VERSION 5.8 ;
BUSBITCHARS "[]" ;
DIVIDERCHAR "/" ;
UNITS
    DATABASE MICRONS 1000 ;
END UNITS

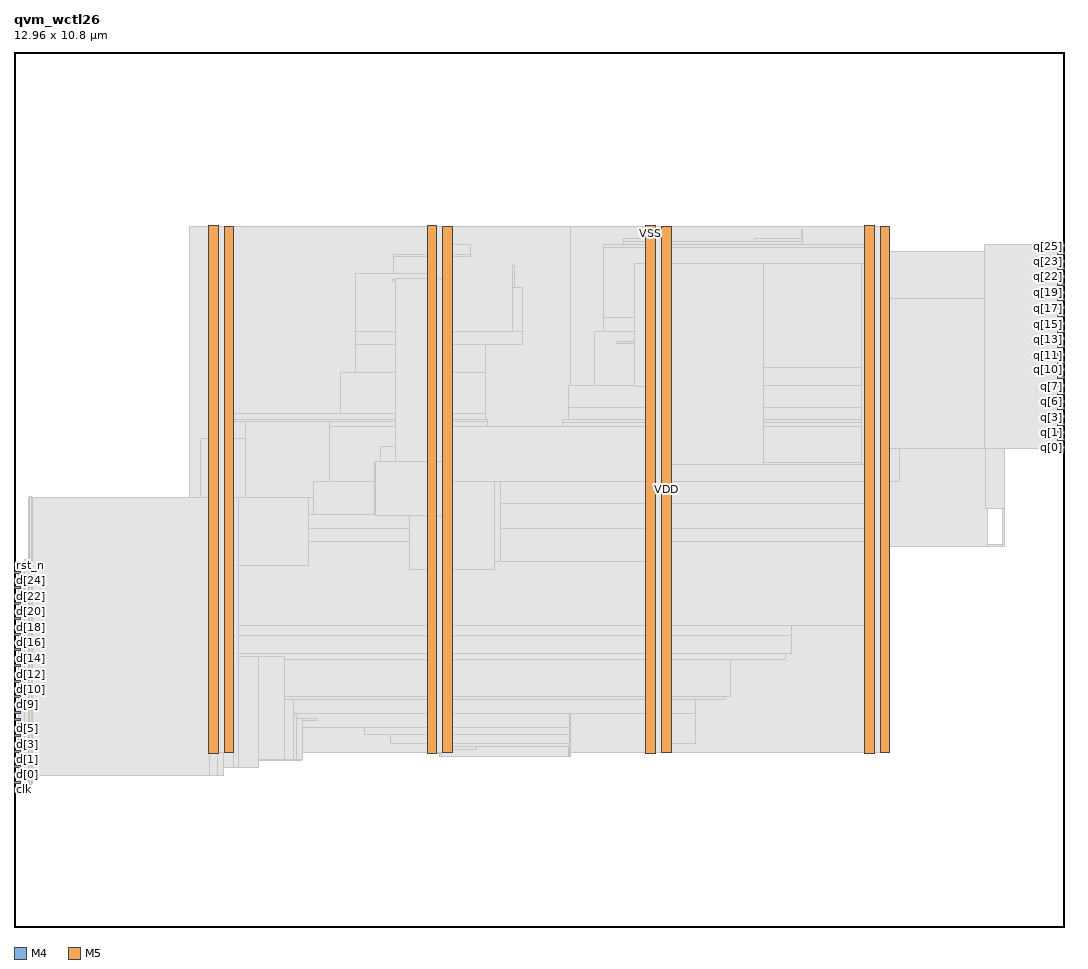
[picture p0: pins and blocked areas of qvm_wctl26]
MACRO qvm_wctl26
  FOREIGN qvm_wctl26 0 0 ;
  CLASS BLOCK ;
  SIZE 12.96 BY 10.8 ;
  PIN clk
    DIRECTION INPUT ;
    USE SIGNAL ;
    PORT
      LAYER M4 ;
        RECT  0 1.776 0.084 1.8 ;
    END
  END clk
  PIN d[0]
    DIRECTION INPUT ;
    USE SIGNAL ;
    PORT
      LAYER M4 ;
        RECT  0 1.872 0.084 1.896 ;
    END
  END d[0]
  PIN d[10]
    DIRECTION INPUT ;
    USE SIGNAL ;
    PORT
      LAYER M4 ;
        RECT  0 2.832 0.084 2.856 ;
    END
  END d[10]
  PIN d[11]
    DIRECTION INPUT ;
    USE SIGNAL ;
    PORT
      LAYER M4 ;
        RECT  0 2.928 0.084 2.952 ;
    END
  END d[11]
  PIN d[12]
    DIRECTION INPUT ;
    USE SIGNAL ;
    PORT
      LAYER M4 ;
        RECT  0 3.024 0.084 3.048 ;
    END
  END d[12]
  PIN d[13]
    DIRECTION INPUT ;
    USE SIGNAL ;
    PORT
      LAYER M4 ;
        RECT  0 3.12 0.084 3.144 ;
    END
  END d[13]
  PIN d[14]
    DIRECTION INPUT ;
    USE SIGNAL ;
    PORT
      LAYER M4 ;
        RECT  0 3.216 0.084 3.24 ;
    END
  END d[14]
  PIN d[15]
    DIRECTION INPUT ;
    USE SIGNAL ;
    PORT
      LAYER M4 ;
        RECT  0 3.312 0.084 3.336 ;
    END
  END d[15]
  PIN d[16]
    DIRECTION INPUT ;
    USE SIGNAL ;
    PORT
      LAYER M4 ;
        RECT  0 3.408 0.084 3.432 ;
    END
  END d[16]
  PIN d[17]
    DIRECTION INPUT ;
    USE SIGNAL ;
    PORT
      LAYER M4 ;
        RECT  0 3.504 0.084 3.528 ;
    END
  END d[17]
  PIN d[18]
    DIRECTION INPUT ;
    USE SIGNAL ;
    PORT
      LAYER M4 ;
        RECT  0 3.6 0.084 3.624 ;
    END
  END d[18]
  PIN d[19]
    DIRECTION INPUT ;
    USE SIGNAL ;
    PORT
      LAYER M4 ;
        RECT  0 3.696 0.084 3.72 ;
    END
  END d[19]
  PIN d[1]
    DIRECTION INPUT ;
    USE SIGNAL ;
    PORT
      LAYER M4 ;
        RECT  0 1.968 0.084 1.992 ;
    END
  END d[1]
  PIN d[20]
    DIRECTION INPUT ;
    USE SIGNAL ;
    PORT
      LAYER M4 ;
        RECT  0 3.792 0.084 3.816 ;
    END
  END d[20]
  PIN d[21]
    DIRECTION INPUT ;
    USE SIGNAL ;
    PORT
      LAYER M4 ;
        RECT  0 3.888 0.084 3.912 ;
    END
  END d[21]
  PIN d[22]
    DIRECTION INPUT ;
    USE SIGNAL ;
    PORT
      LAYER M4 ;
        RECT  0 3.984 0.084 4.008 ;
    END
  END d[22]
  PIN d[23]
    DIRECTION INPUT ;
    USE SIGNAL ;
    PORT
      LAYER M4 ;
        RECT  0 4.08 0.084 4.104 ;
    END
  END d[23]
  PIN d[24]
    DIRECTION INPUT ;
    USE SIGNAL ;
    PORT
      LAYER M4 ;
        RECT  0 4.176 0.084 4.2 ;
    END
  END d[24]
  PIN d[25]
    DIRECTION INPUT ;
    USE SIGNAL ;
    PORT
      LAYER M4 ;
        RECT  0 4.272 0.084 4.296 ;
    END
  END d[25]
  PIN d[2]
    DIRECTION INPUT ;
    USE SIGNAL ;
    PORT
      LAYER M4 ;
        RECT  0 2.064 0.084 2.088 ;
    END
  END d[2]
  PIN d[3]
    DIRECTION INPUT ;
    USE SIGNAL ;
    PORT
      LAYER M4 ;
        RECT  0 2.16 0.084 2.184 ;
    END
  END d[3]
  PIN d[4]
    DIRECTION INPUT ;
    USE SIGNAL ;
    PORT
      LAYER M4 ;
        RECT  0 2.256 0.084 2.28 ;
    END
  END d[4]
  PIN d[5]
    DIRECTION INPUT ;
    USE SIGNAL ;
    PORT
      LAYER M4 ;
        RECT  0 2.352 0.084 2.376 ;
    END
  END d[5]
  PIN d[6]
    DIRECTION INPUT ;
    USE SIGNAL ;
    PORT
      LAYER M4 ;
        RECT  0 2.448 0.084 2.472 ;
    END
  END d[6]
  PIN d[7]
    DIRECTION INPUT ;
    USE SIGNAL ;
    PORT
      LAYER M4 ;
        RECT  0 2.544 0.084 2.568 ;
    END
  END d[7]
  PIN d[8]
    DIRECTION INPUT ;
    USE SIGNAL ;
    PORT
      LAYER M4 ;
        RECT  0 2.64 0.084 2.664 ;
    END
  END d[8]
  PIN d[9]
    DIRECTION INPUT ;
    USE SIGNAL ;
    PORT
      LAYER M4 ;
        RECT  0 2.736 0.084 2.76 ;
    END
  END d[9]
  PIN q[0]
    DIRECTION OUTPUT ;
    USE SIGNAL ;
    PORT
      LAYER M4 ;
        RECT  12.876 5.904 12.96 5.928 ;
    END
  END q[0]
  PIN q[10]
    DIRECTION OUTPUT ;
    USE SIGNAL ;
    PORT
      LAYER M4 ;
        RECT  12.876 6.864 12.96 6.888 ;
    END
  END q[10]
  PIN q[11]
    DIRECTION OUTPUT ;
    USE SIGNAL ;
    PORT
      LAYER M4 ;
        RECT  12.876 6.96 12.96 6.984 ;
    END
  END q[11]
  PIN q[12]
    DIRECTION OUTPUT ;
    USE SIGNAL ;
    PORT
      LAYER M4 ;
        RECT  12.876 7.056 12.96 7.08 ;
    END
  END q[12]
  PIN q[13]
    DIRECTION OUTPUT ;
    USE SIGNAL ;
    PORT
      LAYER M4 ;
        RECT  12.876 7.152 12.96 7.176 ;
    END
  END q[13]
  PIN q[14]
    DIRECTION OUTPUT ;
    USE SIGNAL ;
    PORT
      LAYER M4 ;
        RECT  12.876 7.248 12.96 7.272 ;
    END
  END q[14]
  PIN q[15]
    DIRECTION OUTPUT ;
    USE SIGNAL ;
    PORT
      LAYER M4 ;
        RECT  12.876 7.344 12.96 7.368 ;
    END
  END q[15]
  PIN q[16]
    DIRECTION OUTPUT ;
    USE SIGNAL ;
    PORT
      LAYER M4 ;
        RECT  12.876 7.44 12.96 7.464 ;
    END
  END q[16]
  PIN q[17]
    DIRECTION OUTPUT ;
    USE SIGNAL ;
    PORT
      LAYER M4 ;
        RECT  12.876 7.536 12.96 7.56 ;
    END
  END q[17]
  PIN q[18]
    DIRECTION OUTPUT ;
    USE SIGNAL ;
    PORT
      LAYER M4 ;
        RECT  12.876 7.632 12.96 7.656 ;
    END
  END q[18]
  PIN q[19]
    DIRECTION OUTPUT ;
    USE SIGNAL ;
    PORT
      LAYER M4 ;
        RECT  12.876 7.728 12.96 7.752 ;
    END
  END q[19]
  PIN q[1]
    DIRECTION OUTPUT ;
    USE SIGNAL ;
    PORT
      LAYER M4 ;
        RECT  12.876 6 12.96 6.024 ;
    END
  END q[1]
  PIN q[20]
    DIRECTION OUTPUT ;
    USE SIGNAL ;
    PORT
      LAYER M4 ;
        RECT  12.876 7.824 12.96 7.848 ;
    END
  END q[20]
  PIN q[21]
    DIRECTION OUTPUT ;
    USE SIGNAL ;
    PORT
      LAYER M4 ;
        RECT  12.876 7.92 12.96 7.944 ;
    END
  END q[21]
  PIN q[22]
    DIRECTION OUTPUT ;
    USE SIGNAL ;
    PORT
      LAYER M4 ;
        RECT  12.876 8.016 12.96 8.04 ;
    END
  END q[22]
  PIN q[23]
    DIRECTION OUTPUT ;
    USE SIGNAL ;
    PORT
      LAYER M4 ;
        RECT  12.876 8.112 12.96 8.136 ;
    END
  END q[23]
  PIN q[24]
    DIRECTION OUTPUT ;
    USE SIGNAL ;
    PORT
      LAYER M4 ;
        RECT  12.876 8.208 12.96 8.232 ;
    END
  END q[24]
  PIN q[25]
    DIRECTION OUTPUT ;
    USE SIGNAL ;
    PORT
      LAYER M4 ;
        RECT  12.876 8.304 12.96 8.328 ;
    END
  END q[25]
  PIN q[2]
    DIRECTION OUTPUT ;
    USE SIGNAL ;
    PORT
      LAYER M4 ;
        RECT  12.876 6.096 12.96 6.12 ;
    END
  END q[2]
  PIN q[3]
    DIRECTION OUTPUT ;
    USE SIGNAL ;
    PORT
      LAYER M4 ;
        RECT  12.876 6.192 12.96 6.216 ;
    END
  END q[3]
  PIN q[4]
    DIRECTION OUTPUT ;
    USE SIGNAL ;
    PORT
      LAYER M4 ;
        RECT  12.876 6.288 12.96 6.312 ;
    END
  END q[4]
  PIN q[5]
    DIRECTION OUTPUT ;
    USE SIGNAL ;
    PORT
      LAYER M4 ;
        RECT  12.876 6.384 12.96 6.408 ;
    END
  END q[5]
  PIN q[6]
    DIRECTION OUTPUT ;
    USE SIGNAL ;
    PORT
      LAYER M4 ;
        RECT  12.876 6.48 12.96 6.504 ;
    END
  END q[6]
  PIN q[7]
    DIRECTION OUTPUT ;
    USE SIGNAL ;
    PORT
      LAYER M4 ;
        RECT  12.876 6.576 12.96 6.6 ;
    END
  END q[7]
  PIN q[8]
    DIRECTION OUTPUT ;
    USE SIGNAL ;
    PORT
      LAYER M4 ;
        RECT  12.876 6.672 12.96 6.696 ;
    END
  END q[8]
  PIN q[9]
    DIRECTION OUTPUT ;
    USE SIGNAL ;
    PORT
      LAYER M4 ;
        RECT  12.876 6.768 12.96 6.792 ;
    END
  END q[9]
  PIN qwe
    DIRECTION OUTPUT ;
    USE SIGNAL ;
    PORT
      LAYER M4 ;
        RECT  12.876 8.4 12.96 8.424 ;
    END
  END qwe
  PIN rst_n
    DIRECTION INPUT ;
    USE SIGNAL ;
    PORT
      LAYER M4 ;
        RECT  0 4.368 0.084 4.392 ;
    END
  END rst_n
  PIN we
    DIRECTION INPUT ;
    USE SIGNAL ;
    PORT
      LAYER M4 ;
        RECT  0 4.464 0.084 4.488 ;
    END
  END we
  PIN VDD
    DIRECTION INOUT ;
    USE POWER ;
    PORT
      LAYER M5 ;
        RECT  10.692 2.151 10.812 8.649 ;
        RECT  7.992 2.151 8.112 8.649 ;
        RECT  5.292 2.151 5.412 8.649 ;
        RECT  2.592 2.151 2.712 8.649 ;
    END
  END VDD
  PIN VSS
    DIRECTION INOUT ;
    USE GROUND ;
    PORT
      LAYER M5 ;
        RECT  10.5 2.137 10.62 8.663 ;
        RECT  7.8 2.137 7.92 8.663 ;
        RECT  5.1 2.137 5.22 8.663 ;
        RECT  2.4 2.137 2.52 8.663 ;
    END
  END VSS
  OBS
    LAYER RVTN ;
     RECT  2.16 2.16 10.8 2.295 ;
     RECT  2.16 2.565 10.8 2.835 ;
     RECT  2.16 3.105 10.8 3.375 ;
     RECT  2.16 3.645 10.8 3.915 ;
     RECT  2.16 4.185 10.8 4.455 ;
     RECT  2.16 4.725 10.8 4.995 ;
     RECT  2.16 5.265 10.8 5.535 ;
     RECT  2.16 5.805 10.8 6.075 ;
     RECT  2.16 6.345 10.8 6.615 ;
     RECT  2.16 6.885 10.8 7.155 ;
     RECT  2.16 7.425 10.8 7.695 ;
     RECT  2.16 7.965 10.8 8.235 ;
     RECT  2.16 8.505 10.8 8.64 ;
    LAYER RVTP ;
     RECT  2.16 2.295 10.8 2.565 ;
     RECT  2.16 2.835 10.8 3.105 ;
     RECT  2.16 3.375 10.8 3.645 ;
     RECT  2.16 3.915 10.8 4.185 ;
     RECT  2.16 4.455 10.8 4.725 ;
     RECT  2.16 4.995 10.8 5.265 ;
     RECT  2.16 5.535 10.8 5.805 ;
     RECT  2.16 6.075 10.8 6.345 ;
     RECT  2.16 6.615 10.8 6.885 ;
     RECT  2.16 7.155 10.8 7.425 ;
     RECT  2.16 7.695 10.8 7.965 ;
     RECT  2.16 8.235 10.8 8.505 ;
    LAYER M1 ;
     RECT  2.16 2.151 10.8 8.649 ;
    LAYER M2 ;
     RECT  0.103 3.456 0.203 3.474 ;
     RECT  0.211 3.384 0.347 3.402 ;
     RECT  2.16 2.151 5.251 8.649 ;
     RECT  5.251 2.106 6.863 8.649 ;
     RECT  6.863 2.151 10.8 8.649 ;
     RECT  10.8 2.421 10.812 8.379 ;
     RECT  10.812 4.698 12.011 8.334 ;
     RECT  12.011 5.706 12.047 8.028 ;
     RECT  12.047 5.706 12.083 7.146 ;
     RECT  12.047 8.01 12.119 8.028 ;
     RECT  12.083 6.39 12.155 7.146 ;
     RECT  12.155 6.471 12.191 6.489 ;
     RECT  12.011 4.698 12.227 4.716 ;
    LAYER M3 ;
     RECT  2.556 1.867 2.574 1.963 ;
     RECT  2.556 1.963 3.006 2.059 ;
     RECT  2.556 2.059 3.546 2.143 ;
     RECT  5.256 2.101 5.274 2.143 ;
     RECT  2.415 2.143 3.546 2.155 ;
     RECT  5.115 2.143 5.274 2.191 ;
     RECT  5.115 2.191 5.706 2.227 ;
     RECT  6.84 2.101 6.858 2.227 ;
     RECT  5.115 2.227 6.858 2.263 ;
     RECT  7.815 2.143 7.905 2.263 ;
     RECT  4.644 2.263 6.858 2.371 ;
     RECT  10.515 2.143 10.605 2.413 ;
     RECT  2.304 2.155 3.546 2.461 ;
     RECT  4.32 2.371 6.858 2.461 ;
     RECT  0.216 2.587 0.234 2.635 ;
     RECT  2.304 2.461 6.858 2.641 ;
     RECT  7.815 2.263 8.406 2.641 ;
     RECT  2.304 2.641 8.406 2.803 ;
     RECT  2.304 2.803 8.766 2.839 ;
     RECT  0.144 2.635 0.234 3.211 ;
     RECT  2.304 2.839 8.838 3.307 ;
     RECT  2.304 3.307 9.522 3.379 ;
     RECT  0.144 3.211 0.342 3.403 ;
     RECT  0.108 3.403 0.342 3.437 ;
     RECT  0.108 3.437 0.198 3.479 ;
     RECT  2.304 3.379 9.594 3.595 ;
     RECT  0.18 3.479 0.198 3.677 ;
     RECT  2.196 3.595 9.594 3.721 ;
     RECT  10.515 2.413 10.797 3.721 ;
     RECT  0.144 4.267 0.162 4.541 ;
     RECT  2.196 3.721 10.797 4.757 ;
     RECT  2.304 4.757 10.797 4.919 ;
     RECT  12.204 4.693 12.222 5.161 ;
     RECT  3.6 4.919 10.797 5.225 ;
     RECT  3.708 5.225 10.797 5.501 ;
     RECT  3.888 5.501 10.797 5.503 ;
     RECT  2.304 4.919 2.862 6.035 ;
     RECT  3.888 5.503 10.926 6.179 ;
     RECT  6.768 6.179 10.926 6.221 ;
     RECT  2.415 6.035 2.862 6.241 ;
     RECT  3.888 6.179 5.85 6.241 ;
     RECT  2.415 6.241 5.85 6.269 ;
     RECT  6.768 6.221 10.854 6.269 ;
     RECT  2.415 6.269 5.814 6.341 ;
     RECT  6.84 6.269 10.854 6.413 ;
     RECT  6.84 6.413 10.818 6.683 ;
     RECT  4.032 6.341 5.814 6.845 ;
     RECT  11.988 5.161 12.222 7.085 ;
     RECT  4.212 6.845 5.814 7.195 ;
     RECT  11.988 7.085 12.15 7.339 ;
     RECT  4.212 7.195 6.282 7.349 ;
     RECT  7.164 6.683 10.818 7.349 ;
     RECT  7.272 7.349 10.818 7.529 ;
     RECT  11.916 7.339 12.15 7.661 ;
     RECT  6.156 7.349 6.282 7.889 ;
     RECT  4.212 7.349 5.397 8.069 ;
     RECT  6.156 7.889 6.174 8.159 ;
     RECT  11.988 7.661 12.15 8.237 ;
     RECT  4.68 8.069 5.397 8.275 ;
     RECT  4.68 8.275 5.634 8.303 ;
     RECT  11.988 8.237 12.114 8.333 ;
     RECT  2.415 6.341 2.697 8.387 ;
     RECT  7.272 7.529 10.797 8.387 ;
     RECT  5.115 8.303 5.634 8.429 ;
     RECT  7.272 8.387 10.605 8.429 ;
     RECT  11.988 8.333 12.006 8.429 ;
     RECT  7.524 8.429 9.738 8.465 ;
     RECT  7.524 8.465 7.905 8.501 ;
     RECT  9.144 8.465 9.738 8.501 ;
     RECT  9.72 8.501 9.738 8.609 ;
     RECT  2.415 8.387 2.505 8.657 ;
     RECT  5.115 8.429 5.205 8.657 ;
     RECT  7.815 8.501 7.905 8.657 ;
     RECT  10.515 8.429 10.605 8.657 ;
    LAYER M4 ;
     RECT  0.06 1.776 0.133 4.488 ;
     RECT  0.133 1.776 0.181 4.536 ;
     RECT  0.181 1.776 0.227 5.304 ;
     RECT  0.227 1.872 2.408 5.304 ;
     RECT  2.408 1.872 2.512 8.652 ;
     RECT  2.512 1.872 2.585 8.382 ;
     RECT  2.585 1.968 2.704 8.382 ;
     RECT  2.704 1.968 2.765 5.304 ;
     RECT  2.765 1.968 3.017 3.336 ;
     RECT  3.017 2.064 3.341 3.336 ;
     RECT  3.341 2.064 3.449 2.808 ;
     RECT  3.449 2.064 3.485 2.616 ;
     RECT  3.485 2.064 3.557 2.568 ;
     RECT  2.765 4.464 3.629 5.304 ;
     RECT  3.629 5.088 3.697 5.304 ;
     RECT  3.557 2.544 3.737 2.568 ;
     RECT  3.697 5.088 4.453 5.496 ;
     RECT  4.453 5.088 4.525 5.736 ;
     RECT  4.525 5.088 4.885 5.928 ;
     RECT  4.885 4.416 5.108 5.928 ;
     RECT  4.669 7.968 5.108 7.992 ;
     RECT  5.108 2.148 5.212 8.652 ;
     RECT  5.212 2.418 5.404 8.382 ;
     RECT  5.404 4.416 5.933 5.496 ;
     RECT  5.933 4.512 6.005 5.496 ;
     RECT  7.441 7.2 7.657 7.224 ;
     RECT  6.005 4.512 7.808 4.92 ;
     RECT  7.657 6.672 7.808 8.184 ;
     RECT  7.808 2.148 7.912 8.652 ;
     RECT  7.912 2.418 8.104 8.382 ;
     RECT  8.104 5.712 9.245 8.184 ;
     RECT  9.245 5.712 10.465 5.736 ;
     RECT  9.245 6.912 10.465 8.184 ;
     RECT  10.465 5.712 10.508 8.184 ;
     RECT  10.508 2.148 10.612 8.652 ;
     RECT  10.612 2.418 10.804 8.382 ;
     RECT  10.804 5.904 11.977 7.752 ;
     RECT  11.977 5.904 12.924 8.424 ;
    LAYER M5 ;
     RECT  2.4 2.137 2.52 2.151 ;
     RECT  5.1 2.137 5.22 2.151 ;
     RECT  7.8 2.137 7.92 2.151 ;
     RECT  10.5 2.137 10.62 2.151 ;
     RECT  5.1 2.151 5.412 5.077 ;
     RECT  0.192 1.765 0.216 5.315 ;
     RECT  4.464 5.077 5.412 5.747 ;
     RECT  4.704 5.747 5.412 8.003 ;
     RECT  2.4 2.151 2.712 8.649 ;
     RECT  5.1 8.003 5.412 8.649 ;
     RECT  7.8 2.151 8.112 8.649 ;
     RECT  10.5 2.151 10.812 8.649 ;
     RECT  2.4 8.649 2.52 8.663 ;
     RECT  5.1 8.649 5.22 8.663 ;
     RECT  7.8 8.649 7.92 8.663 ;
     RECT  10.5 8.649 10.62 8.663 ;
  END
END qvm_wctl26
END LIBRARY
